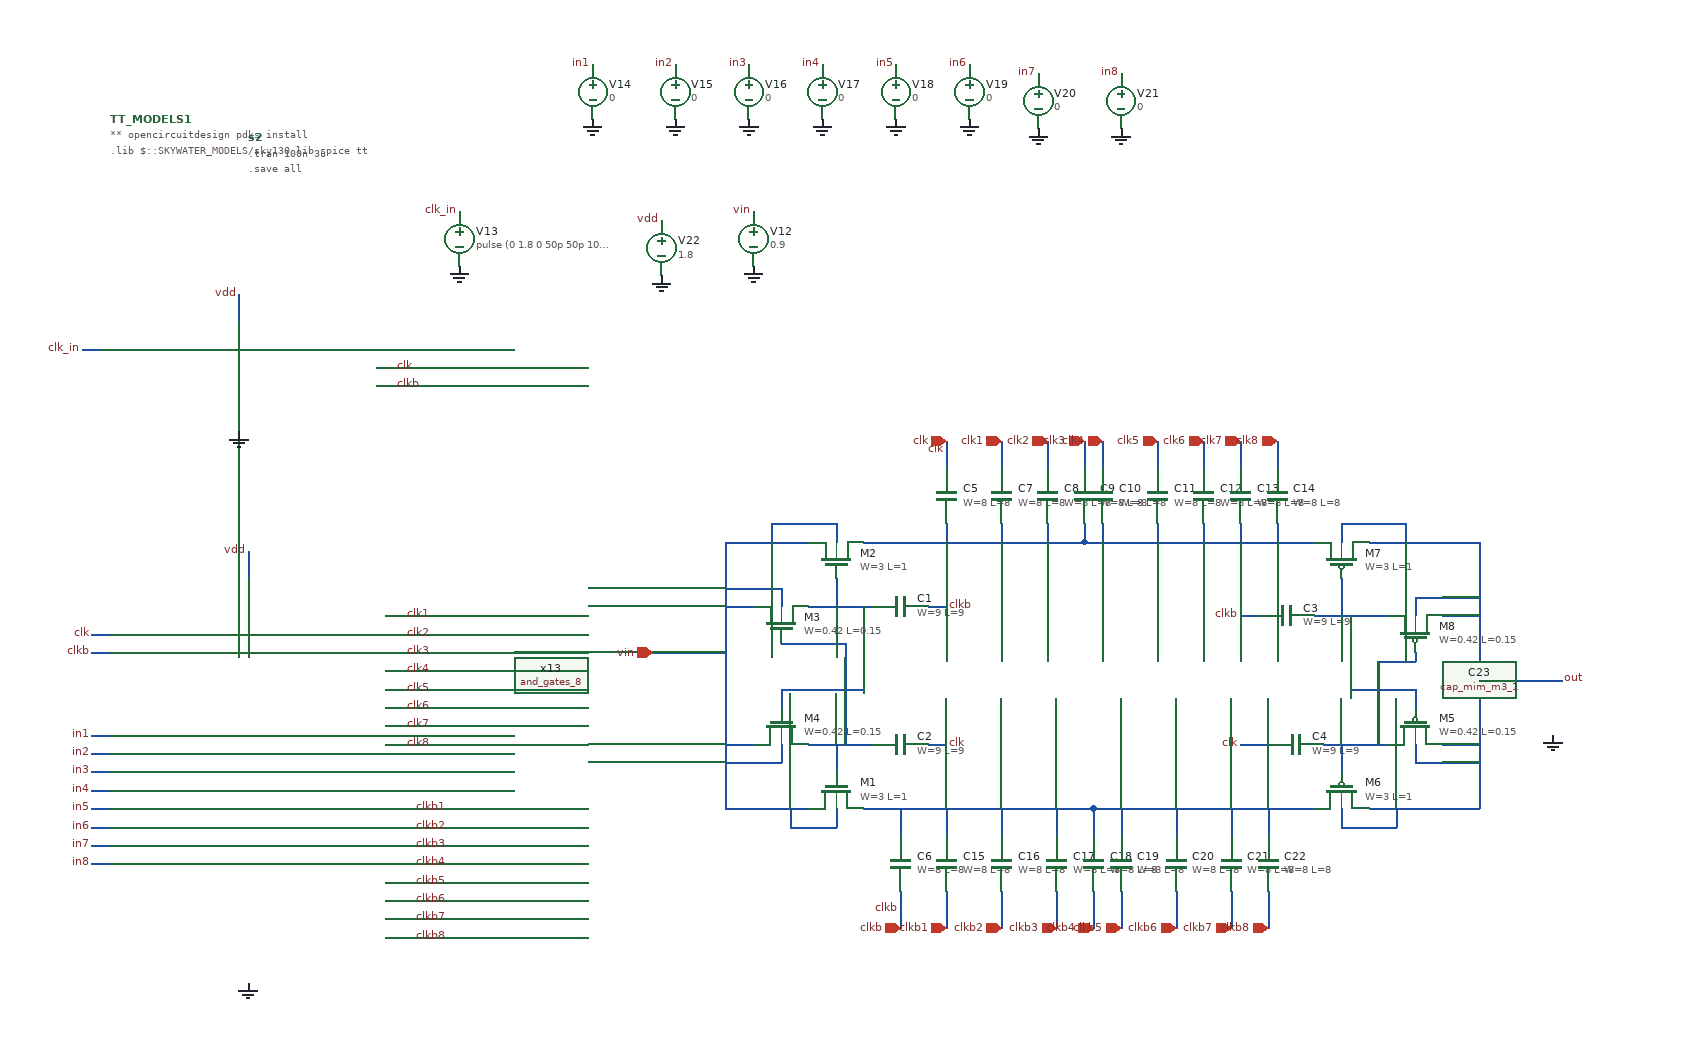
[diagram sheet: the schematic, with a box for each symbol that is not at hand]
v {xschem version=3.4.4 file_version=1.2
}
G {}
K {}
V {}
S {}
E {}
N -640 20 -620 20 {
lab=clk1}
N -640 40 -620 40 {
lab=clk2}
N -640 60 -620 60 {
lab=clk3}
N -640 80 -620 80 {
lab=clk4}
N -640 100 -620 100 {
lab=clk5}
N -640 120 -620 120 {
lab=clk6}
N -640 140 -620 140 {
lab=clk7}
N -640 160 -620 160 {
lab=clk8}
N -640 230 -610 230 {
lab=clkb1}
N -640 250 -610 250 {
lab=clkb2}
N -640 270 -610 270 {
lab=clkb3}
N -640 290 -610 290 {
lab=clkb4}
N -640 310 -610 310 {
lab=clkb5}
N -640 330 -610 330 {
lab=clkb6}
N -640 350 -610 350 {
lab=clkb7}
N -640 370 -610 370 {
lab=clkb8}
N -960 40 -940 40 {
lab=clk}
N -960 60 -940 60 {
lab=clkb}
N -960 150 -940 150 {
lab=in1}
N -960 170 -940 170 {
lab=in2}
N -960 190 -940 190 {
lab=in3}
N -960 210 -940 210 {
lab=in4}
N -960 230 -940 230 {
lab=in5}
N -960 250 -940 250 {
lab=in6}
N -960 270 -940 270 {
lab=in7}
N -960 290 -940 290 {
lab=in8}
N -790 -50 -790 -20 {
lab=vdd}
N -800 -330 -800 -300 {
lab=vdd}
N -970 -270 -950 -270 {
lab=clk_in}
N -650 -250 -630 -250 {
lab=clk}
N -650 -230 -630 -230 {
lab=clkb}
N -120 -60 120 -60 {
lab=#net1}
N 360 -60 370 -60 {
lab=#net1}
N -270 -60 -180 -60 {
lab=vin}
N -270 -60 -270 230 {
lab=vin}
N -270 230 -180 230 {
lab=vin}
N -120 230 130 230 {
lab=#net2}
N 430 230 550 230 {
lab=out}
N 550 -60 550 230 {
lab=out}
N 430 -60 550 -60 {
lab=out}
N 510 20 550 20 {
lab=out}
N 510 160 550 160 {
lab=out}
N -270 10 -240 10 {
lab=vin}
N -270 160 -240 160 {
lab=vin}
N -150 -80 -150 -60 {
lab=vin}
N -220 -80 -150 -80 {
lab=vin}
N -220 -80 -220 -60 {
lab=vin}
N 400 -80 400 -60 {
lab=out}
N 400 -80 470 -80 {
lab=out}
N 470 -80 470 -60 {
lab=out}
N 480 0 480 20 {
lab=out}
N 480 0 550 0 {
lab=out}
N 480 160 480 180 {
lab=out}
N 480 180 550 180 {
lab=out}
N 400 230 400 240 {
lab=out}
N 400 240 400 250 {
lab=out}
N 400 250 460 250 {
lab=out}
N 460 230 460 250 {
lab=out}
N -150 230 -150 250 {
lab=vin}
N -200 250 -150 250 {
lab=vin}
N -200 230 -200 250 {
lab=vin}
N -210 160 -210 180 {
lab=vin}
N -270 180 -210 180 {
lab=vin}
N -210 -10 -210 10 {
lab=vin}
N -270 -10 -210 -10 {
lab=vin}
N -180 10 -110 10 {
lab=#net3}
N -150 -20 -150 10 {
lab=#net3}
N -180 160 -110 160 {
lab=#net4}
N -150 160 -150 190 {
lab=#net4}
N 370 20 450 20 {
lab=#net5}
N 400 -20 400 20 {
lab=#net5}
N 380 160 450 160 {
lab=#net6}
N 400 160 400 190 {
lab=#net6}
N -30 -80 -30 -60 {
lab=#net1}
N -80 230 -80 260 {
lab=#net2}
N -30 -170 -30 -140 {
lab=clk}
N -80 320 -80 360 {
lab=clkb}
N -50 160 -30 160 {
lab=clk}
N -50 10 -30 10 {
lab=clkb}
N 290 20 310 20 {
lab=clkb}
N 290 160 320 160 {
lab=clk}
N -210 50 -140 50 {
lab=#net4}
N -140 50 -140 160 {
lab=#net4}
N -210 100 -210 120 {
lab=#net3}
N -210 100 -120 100 {
lab=#net3}
N -120 10 -120 100 {
lab=#net3}
N 480 60 480 70 {
lab=#net6}
N 440 70 480 70 {
lab=#net6}
N 440 70 440 160 {
lab=#net6}
N 480 100 480 120 {
lab=#net5}
N 410 100 480 100 {
lab=#net5}
N 410 20 410 100 {
lab=#net5}
N 120 -60 360 -60 {
lab=#net1}
N 130 230 370 230 {
lab=#net2}
N 30 -80 30 -60 {
lab=#net1}
N 30 -170 30 -140 {
lab=clk1}
N 80 -80 80 -60 {
lab=#net1}
N 80 -170 80 -140 {
lab=clk2}
N 120 -80 120 -60 {
lab=#net1}
N 120 -170 120 -140 {
lab=clk3}
N 140 -80 140 -60 {
lab=#net1}
N 140 -170 140 -140 {
lab=clk4}
N 200 -80 200 -60 {
lab=#net1}
N 200 -170 200 -140 {
lab=clk5}
N 250 -80 250 -60 {
lab=#net1}
N 250 -170 250 -140 {
lab=clk6}
N 290 -80 290 -60 {
lab=#net1}
N 290 -170 290 -140 {
lab=clk7}
N 330 -80 330 -60 {
lab=#net1}
N 330 -170 330 -140 {
lab=clk8}
N -30 230 -30 260 {
lab=#net2}
N -30 320 -30 360 {
lab=clkb1}
N 30 230 30 260 {
lab=#net2}
N 30 320 30 360 {
lab=clkb2}
N 90 230 90 260 {
lab=#net2}
N 90 320 90 360 {
lab=clkb3}
N 130 230 130 260 {
lab=#net2}
N 130 320 130 360 {
lab=clkb4}
N 160 230 160 260 {
lab=#net2}
N 160 320 160 360 {
lab=clkb5}
N 220 230 220 260 {
lab=#net2}
N 220 320 220 360 {
lab=clkb6}
N 280 230 280 260 {
lab=#net2}
N 280 320 280 360 {
lab=clkb7}
N 320 230 320 260 {
lab=#net2}
N 320 320 320 360 {
lab=clkb8}
N -350 60 -270 60 {
lab=vin}
N 550 90 640 90 {
lab=out}
C {and_gates_8.sym} -790 200 0 0 {name=x13}
C {devices/lab_pin.sym} -620 20 2 0 {name=p238 sig_type=std_logic lab=clk1}
C {devices/lab_pin.sym} -620 40 2 0 {name=p239 sig_type=std_logic lab=clk2}
C {devices/lab_pin.sym} -620 60 2 0 {name=p240 sig_type=std_logic lab=clk3}
C {devices/lab_pin.sym} -620 80 2 0 {name=p241 sig_type=std_logic lab=clk4}
C {devices/lab_pin.sym} -620 100 2 0 {name=p242 sig_type=std_logic lab=clk5}
C {devices/lab_pin.sym} -620 120 2 0 {name=p243 sig_type=std_logic lab=clk6}
C {devices/lab_pin.sym} -620 140 2 0 {name=p244 sig_type=std_logic lab=clk7}
C {devices/lab_pin.sym} -620 160 2 0 {name=p245 sig_type=std_logic lab=clk8}
C {devices/lab_pin.sym} -610 230 0 1 {name=p246 sig_type=std_logic lab=clkb1}
C {devices/lab_pin.sym} -610 250 0 1 {name=p247 sig_type=std_logic lab=clkb2}
C {devices/lab_pin.sym} -610 270 0 1 {name=p248 sig_type=std_logic lab=clkb3}
C {devices/lab_pin.sym} -610 290 0 1 {name=p249 sig_type=std_logic lab=clkb4}
C {devices/lab_pin.sym} -610 310 0 1 {name=p250 sig_type=std_logic lab=clkb5}
C {devices/lab_pin.sym} -610 330 0 1 {name=p251 sig_type=std_logic lab=clkb6}
C {devices/lab_pin.sym} -610 350 0 1 {name=p252 sig_type=std_logic lab=clkb7}
C {devices/lab_pin.sym} -610 370 0 1 {name=p253 sig_type=std_logic lab=clkb8}
C {devices/lab_pin.sym} -960 40 0 0 {name=p254 sig_type=std_logic lab=clk}
C {devices/lab_pin.sym} -960 60 0 0 {name=p255 sig_type=std_logic lab=clkb}
C {devices/lab_pin.sym} -960 150 0 0 {name=p256 sig_type=std_logic lab=in1}
C {devices/lab_pin.sym} -960 170 0 0 {name=p257 sig_type=std_logic lab=in2}
C {devices/lab_pin.sym} -960 190 0 0 {name=p258 sig_type=std_logic lab=in3}
C {devices/lab_pin.sym} -960 210 0 0 {name=p259 sig_type=std_logic lab=in4}
C {devices/lab_pin.sym} -960 230 0 0 {name=p260 sig_type=std_logic lab=in5}
C {devices/lab_pin.sym} -960 250 0 0 {name=p261 sig_type=std_logic lab=in6}
C {devices/lab_pin.sym} -960 270 0 0 {name=p262 sig_type=std_logic lab=in7}
C {devices/lab_pin.sym} -960 290 0 0 {name=p263 sig_type=std_logic lab=in8}
C {devices/lab_pin.sym} -790 -50 1 0 {name=p264 sig_type=std_logic lab=vdd}
C {devices/lab_pin.sym} -800 -330 1 0 {name=p27 sig_type=std_logic lab=vdd}
C {devices/lab_pin.sym} -970 -270 0 0 {name=p28 sig_type=std_logic lab=clk_in}
C {devices/lab_pin.sym} -630 -250 2 0 {name=p29 sig_type=std_logic lab=clk}
C {devices/lab_pin.sym} -630 -230 2 0 {name=p30 sig_type=std_logic lab=clkb}
C {devices/vsource.sym} -240 -390 0 0 {name=V12 value=0.9}
C {devices/lab_pin.sym} -240 -420 1 0 {name=p33 sig_type=std_logic lab=vin}
C {devices/gnd.sym} -240 -360 0 0 {name=l1 lab=GND}
C {devices/vsource.sym} -560 -390 0 0 {name=V13 value="pulse (0 1.8 0 50p 50p 10n 20n)"}
C {devices/lab_pin.sym} -560 -420 1 0 {name=p34 sig_type=std_logic lab=clk_in}
C {devices/gnd.sym} -560 -360 0 0 {name=l13 lab=GND}
C {devices/vsource.sym} -415 -550 0 0 {name=V14 value=0}
C {devices/lab_pin.sym} -415 -580 1 0 {name=p35 sig_type=std_logic lab=in1
value=0}
C {devices/gnd.sym} -415 -520 0 0 {name=l14 lab=GND
value=0}
C {devices/vsource.sym} -325 -550 0 0 {name=V15 value=0}
C {devices/lab_pin.sym} -325 -580 1 0 {name=p36 sig_type=std_logic lab=in2
value=0}
C {devices/gnd.sym} -325 -520 0 0 {name=l15 lab=GND
value=0}
C {devices/vsource.sym} -245 -550 0 0 {name=V16 value=0}
C {devices/lab_pin.sym} -245 -580 1 0 {name=p37 sig_type=std_logic lab=in3
value=0}
C {devices/gnd.sym} -245 -520 0 0 {name=l16 lab=GND
value=0}
C {devices/vsource.sym} -165 -550 0 0 {name=V17 value=0}
C {devices/lab_pin.sym} -165 -580 1 0 {name=p38 sig_type=std_logic lab=in4
value=0}
C {devices/gnd.sym} -165 -520 0 0 {name=l17 lab=GND
value=0}
C {devices/vsource.sym} -85 -550 0 0 {name=V18 value=0
}
C {devices/lab_pin.sym} -85 -580 1 0 {name=p39 sig_type=std_logic lab=in5
value=0}
C {devices/gnd.sym} -85 -520 0 0 {name=l18 lab=GND
value=0}
C {devices/vsource.sym} -5 -550 0 0 {name=V19 value=0}
C {devices/lab_pin.sym} -5 -580 1 0 {name=p40 sig_type=std_logic lab=in6
value=0}
C {devices/gnd.sym} -5 -520 0 0 {name=l19 lab=GND
value=0}
C {devices/vsource.sym} 70 -540 0 0 {name=V20 value=0}
C {devices/lab_pin.sym} 70 -570 1 0 {name=p41 sig_type=std_logic lab=in7
value=0}
C {devices/gnd.sym} 70 -510 0 0 {name=l20 lab=GND
value=0}
C {devices/vsource.sym} 160 -540 0 0 {name=V21 value=0}
C {devices/lab_pin.sym} 160 -570 1 0 {name=p42 sig_type=std_logic lab=in8
value=0}
C {devices/gnd.sym} 160 -510 0 0 {name=l21 lab=GND
value=0}
C {devices/vsource.sym} -340 -380 0 0 {name=V22 value=1.8}
C {devices/lab_pin.sym} -340 -410 1 0 {name=p43 sig_type=std_logic lab=vdd}
C {devices/gnd.sym} -340 -350 0 0 {name=l22 lab=GND}
C {devices/code.sym} -940 -520 0 0 {name=TT_MODELS1
only_toplevel=true
format="tcleval( @value )"
value="
** opencircuitdesign pdks install
.lib $::SKYWATER_MODELS/sky130.lib.spice tt

"
spice_ignore=false}
C {devices/code_shown.sym} -790 -500 0 0 {name=s2 only_toplevel=false value="
.tran 100n 3u
.save all
"}
C {devices/gnd.sym} -800 -180 0 0 {name=l2 lab=GND}
C {devices/gnd.sym} -790 420 0 0 {name=l3 lab=GND}
C {sky130_fd_pr/nfet_01v8.sym} -150 -40 1 1 {name=M2
L=1
W=3
nf=1 
mult=1
ad="'int((nf+1)/2) * W/nf * 0.29'" 
pd="'2*int((nf+1)/2) * (W/nf + 0.29)'"
as="'int((nf+2)/2) * W/nf * 0.29'" 
ps="'2*int((nf+2)/2) * (W/nf + 0.29)'"
nrd="'0.29 / W'" nrs="'0.29 / W'"
sa=0 sb=0 sd=0
model=nfet_01v8
spiceprefix=X
}
C {sky130_fd_pr/nfet_01v8.sym} -150 210 1 0 {name=M1
L=1
W=3
nf=1 
mult=1
ad="'int((nf+1)/2) * W/nf * 0.29'" 
pd="'2*int((nf+1)/2) * (W/nf + 0.29)'"
as="'int((nf+2)/2) * W/nf * 0.29'" 
ps="'2*int((nf+2)/2) * (W/nf + 0.29)'"
nrd="'0.29 / W'" nrs="'0.29 / W'"
sa=0 sb=0 sd=0
model=nfet_01v8
spiceprefix=X
}
C {sky130_fd_pr/nfet_01v8.sym} -210 30 1 1 {name=M3
L=0.15
W=0.42
nf=1 
mult=1
ad="'int((nf+1)/2) * W/nf * 0.29'" 
pd="'2*int((nf+1)/2) * (W/nf + 0.29)'"
as="'int((nf+2)/2) * W/nf * 0.29'" 
ps="'2*int((nf+2)/2) * (W/nf + 0.29)'"
nrd="'0.29 / W'" nrs="'0.29 / W'"
sa=0 sb=0 sd=0
model=nfet_01v8
spiceprefix=X
}
C {sky130_fd_pr/nfet_01v8.sym} -210 140 1 0 {name=M4
L=0.15
W=0.42
nf=1 
mult=1
ad="'int((nf+1)/2) * W/nf * 0.29'" 
pd="'2*int((nf+1)/2) * (W/nf + 0.29)'"
as="'int((nf+2)/2) * W/nf * 0.29'" 
ps="'2*int((nf+2)/2) * (W/nf + 0.29)'"
nrd="'0.29 / W'" nrs="'0.29 / W'"
sa=0 sb=0 sd=0
model=nfet_01v8
spiceprefix=X
}
C {sky130_fd_pr/pfet_01v8.sym} 480 140 1 0 {name=M5
L=0.15
W=0.42
nf=1
mult=1
ad="'int((nf+1)/2) * W/nf * 0.29'" 
pd="'2*int((nf+1)/2) * (W/nf + 0.29)'"
as="'int((nf+2)/2) * W/nf * 0.29'" 
ps="'2*int((nf+2)/2) * (W/nf + 0.29)'"
nrd="'0.29 / W'" nrs="'0.29 / W'"
sa=0 sb=0 sd=0
model=pfet_01v8
spiceprefix=X
}
C {sky130_fd_pr/pfet_01v8.sym} 400 210 1 0 {name=M6
L=1
W=3
nf=1
mult=1
ad="'int((nf+1)/2) * W/nf * 0.29'" 
pd="'2*int((nf+1)/2) * (W/nf + 0.29)'"
as="'int((nf+2)/2) * W/nf * 0.29'" 
ps="'2*int((nf+2)/2) * (W/nf + 0.29)'"
nrd="'0.29 / W'" nrs="'0.29 / W'"
sa=0 sb=0 sd=0
model=pfet_01v8
spiceprefix=X
}
C {sky130_fd_pr/pfet_01v8.sym} 400 -40 1 1 {name=M7
L=1
W=3
nf=1
mult=1
ad="'int((nf+1)/2) * W/nf * 0.29'" 
pd="'2*int((nf+1)/2) * (W/nf + 0.29)'"
as="'int((nf+2)/2) * W/nf * 0.29'" 
ps="'2*int((nf+2)/2) * (W/nf + 0.29)'"
nrd="'0.29 / W'" nrs="'0.29 / W'"
sa=0 sb=0 sd=0
model=pfet_01v8
spiceprefix=X
}
C {sky130_fd_pr/pfet_01v8.sym} 480 40 1 1 {name=M8
L=0.15
W=0.42
nf=1
mult=1
ad="'int((nf+1)/2) * W/nf * 0.29'" 
pd="'2*int((nf+1)/2) * (W/nf + 0.29)'"
as="'int((nf+2)/2) * W/nf * 0.29'" 
ps="'2*int((nf+2)/2) * (W/nf + 0.29)'"
nrd="'0.29 / W'" nrs="'0.29 / W'"
sa=0 sb=0 sd=0
model=pfet_01v8
spiceprefix=X
}
C {sky130_fd_pr/cap_mim_m3_1.sym} -80 10 3 0 {name=C1 model=cap_mim_m3_1 W=9 L=9 MF=1 spiceprefix=X}
C {sky130_fd_pr/cap_mim_m3_1.sym} -80 160 3 0 {name=C2 model=cap_mim_m3_1 W=9 L=9 MF=1 spiceprefix=X}
C {sky130_fd_pr/cap_mim_m3_1.sym} 340 20 1 0 {name=C3 model=cap_mim_m3_1 W=9 L=9 MF=1 spiceprefix=X}
C {sky130_fd_pr/cap_mim_m3_1.sym} 350 160 1 0 {name=C4 model=cap_mim_m3_1 W=9 L=9 MF=1 spiceprefix=X}
C {sky130_fd_pr/cap_mim_m3_1.sym} -30 -110 2 0 {name=C5 model=cap_mim_m3_1 W=8 L=8 MF=1 spiceprefix=X}
C {sky130_fd_pr/cap_mim_m3_1.sym} -80 290 0 0 {name=C6 model=cap_mim_m3_1 W=8 L=8 MF=1 spiceprefix=X}
C {sky130_fd_pr/cap_mim_m3_1.sym} 30 -110 2 0 {name=C7 model=cap_mim_m3_1 W=8 L=8 MF=1 spiceprefix=X}
C {sky130_fd_pr/cap_mim_m3_1.sym} 80 -110 2 0 {name=C8 model=cap_mim_m3_1 W=8 L=8 MF=1 spiceprefix=X}
C {sky130_fd_pr/cap_mim_m3_1.sym} 120 -110 2 0 {name=C9 model=cap_mim_m3_1 W=8 L=8 MF=1 spiceprefix=X}
C {sky130_fd_pr/cap_mim_m3_1.sym} 140 -110 2 0 {name=C10 model=cap_mim_m3_1 W=8 L=8 MF=1 spiceprefix=X}
C {sky130_fd_pr/cap_mim_m3_1.sym} 200 -110 2 0 {name=C11 model=cap_mim_m3_1 W=8 L=8 MF=1 spiceprefix=X}
C {sky130_fd_pr/cap_mim_m3_1.sym} 250 -110 2 0 {name=C12 model=cap_mim_m3_1 W=8 L=8 MF=1 spiceprefix=X}
C {sky130_fd_pr/cap_mim_m3_1.sym} 290 -110 2 0 {name=C13 model=cap_mim_m3_1 W=8 L=8 MF=1 spiceprefix=X}
C {sky130_fd_pr/cap_mim_m3_1.sym} 330 -110 2 0 {name=C14 model=cap_mim_m3_1 W=8 L=8 MF=1 spiceprefix=X}
C {sky130_fd_pr/cap_mim_m3_1.sym} -30 290 0 0 {name=C15 model=cap_mim_m3_1 W=8 L=8 MF=1 spiceprefix=X}
C {sky130_fd_pr/cap_mim_m3_1.sym} 30 290 0 0 {name=C16 model=cap_mim_m3_1 W=8 L=8 MF=1 spiceprefix=X}
C {sky130_fd_pr/cap_mim_m3_1.sym} 90 290 0 0 {name=C17 model=cap_mim_m3_1 W=8 L=8 MF=1 spiceprefix=X}
C {sky130_fd_pr/cap_mim_m3_1.sym} 130 290 0 0 {name=C18 model=cap_mim_m3_1 W=8 L=8 MF=1 spiceprefix=X}
C {sky130_fd_pr/cap_mim_m3_1.sym} 160 290 0 0 {name=C19 model=cap_mim_m3_1 W=8 L=8 MF=1 spiceprefix=X}
C {sky130_fd_pr/cap_mim_m3_1.sym} 220 290 0 0 {name=C20 model=cap_mim_m3_1 W=8 L=8 MF=1 spiceprefix=X}
C {sky130_fd_pr/cap_mim_m3_1.sym} 280 290 0 0 {name=C21 model=cap_mim_m3_1 W=8 L=8 MF=1 spiceprefix=X}
C {sky130_fd_pr/cap_mim_m3_1.sym} 320 290 0 0 {name=C22 model=cap_mim_m3_1 W=8 L=8 MF=1 spiceprefix=X}
C {devices/lab_pin.sym} 290 20 0 0 {name=p1 sig_type=std_logic lab=clkb}
C {devices/lab_pin.sym} -30 10 2 0 {name=p2 sig_type=std_logic lab=clkb}
C {devices/lab_pin.sym} -30 160 2 0 {name=p3 sig_type=std_logic lab=clk}
C {devices/lab_pin.sym} 290 160 0 0 {name=p4 sig_type=std_logic lab=clk}
C {devices/lab_pin.sym} -30 -160 0 0 {name=p7 sig_type=std_logic lab=clk
W=7
L=7}
C {devices/lab_pin.sym} -80 340 0 0 {name=p6 sig_type=std_logic lab=clkb
W=8
L=8}
C {devices/ipin.sym} -350 60 0 0 {name=p5 lab=vin}
C {devices/ipin.sym} -30 -170 1 0 {name=p9 lab=clk}
C {devices/ipin.sym} 30 -170 1 0 {name=p8 lab=clk1}
C {devices/ipin.sym} 80 -170 1 0 {name=p10 lab=clk2}
C {devices/ipin.sym} 120 -170 1 0 {name=p11 lab=clk3}
C {devices/ipin.sym} 140 -170 1 0 {name=p12 lab=clk4}
C {devices/ipin.sym} 200 -170 1 0 {name=p13 lab=clk5}
C {devices/ipin.sym} 250 -170 1 0 {name=p14 lab=clk6}
C {devices/ipin.sym} 290 -170 1 0 {name=p15 lab=clk7}
C {devices/ipin.sym} 330 -170 1 0 {name=p16 lab=clk8}
C {devices/ipin.sym} -80 360 3 0 {name=p17 lab=clkb}
C {devices/ipin.sym} -30 360 3 0 {name=p18 lab=clkb1}
C {devices/ipin.sym} 30 360 3 0 {name=p19 lab=clkb2}
C {devices/ipin.sym} 90 360 3 0 {name=p20 lab=clkb3}
C {devices/ipin.sym} 130 360 3 0 {name=p21 lab=clkb4}
C {devices/ipin.sym} 160 360 3 0 {name=p22 lab=clkb5}
C {devices/ipin.sym} 220 360 3 0 {name=p23 lab=clkb6}
C {devices/ipin.sym} 280 360 3 0 {name=p24 lab=clkb7}
C {devices/ipin.sym} 320 360 3 0 {name=p25 lab=clkb8}
C {devices/lab_pin.sym} 640 90 2 0 {name=p154 sig_type=std_logic lab=out}
C {sky130_fd_pr/cap_mim_m3_1.sym} 630 120 0 0 {name=C23 model=cap_mim_m3_1 W=20 L=20 MF=1 spiceprefix=X}
C {devices/gnd.sym} 630 150 0 0 {name=l36 lab=GND}
